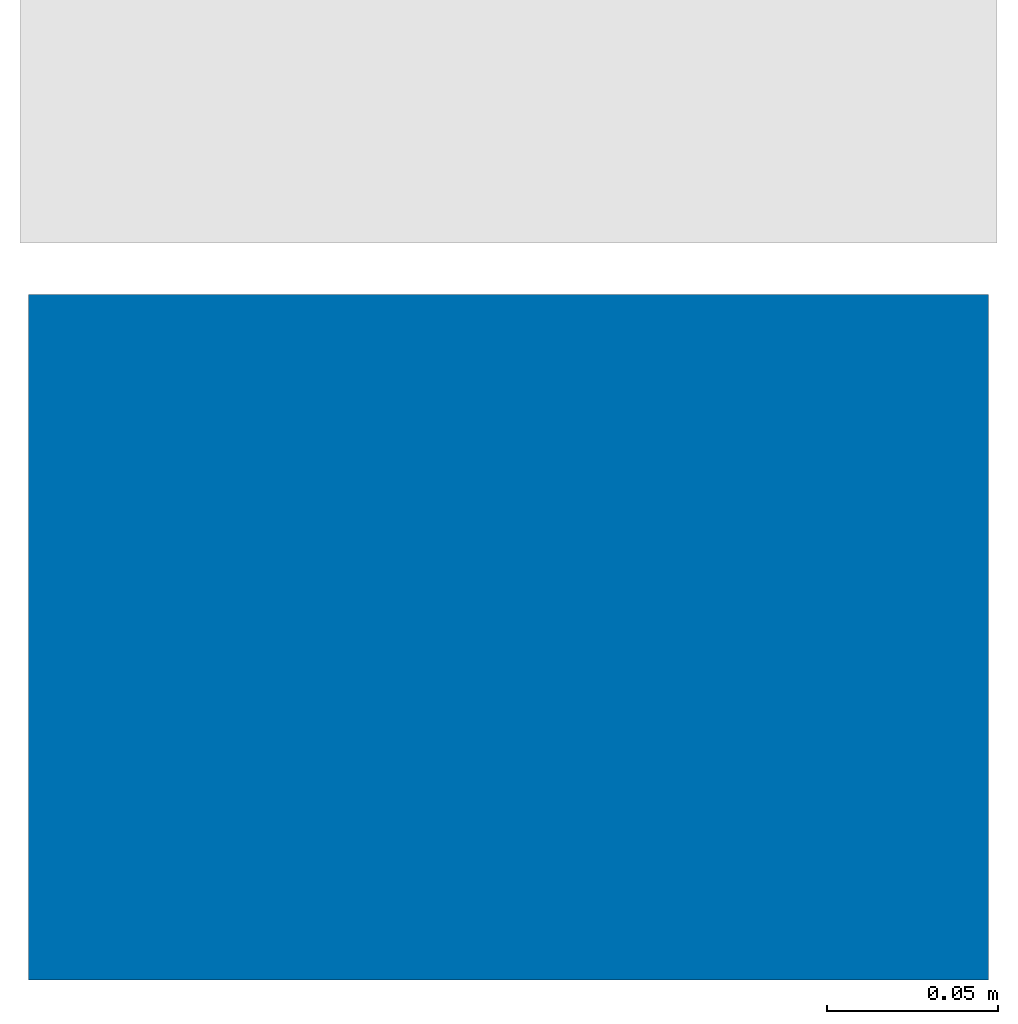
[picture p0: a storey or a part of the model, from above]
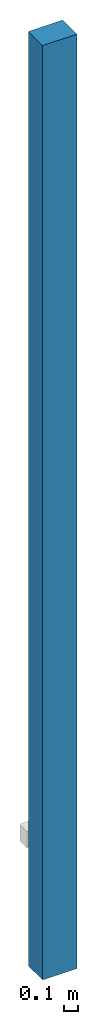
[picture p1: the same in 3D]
Properties of the parts of a building model (IFC2X3)

# File
Description: ViewDefinition [CoordinationView]
File name: Project Number
Time: 2017-11-08T12:43:37
Written by: The EXPRESS Data Manager Version 5.02.0100.07 : 28 Aug 2013
Made in: 20140606_1530(x64) - Exporter 2015.0.2014.0606 - Default UI
Comment: STEP Physical File produced by: The EXPRESS Data Manager Version 5.02.0100.07 : 28 Aug 2013 * Module: EDMstepFileFactory/EDMstandAlone * Creation date: Wed Nov 08 12:43:37 2017 * Host: DESKTOP-FI6EGIK * Database: C:\Users\CERTIF~1\AppData\Local\Temp\{4086A7C5-652F-4AB4-8ED6-AFAA93B8A9EB}\ifc * Database version: 5507 * Database creation date: Wed Nov 08 12:43:37 2017 * Schema: IFC2X3 * Model: DataRepository.ifc * Model creation date: Wed Nov 08 12:43:37 2017 * Header model: DataRepository.ifc_HeaderModel * Header model creation date: Wed Nov 08 12:43:37 2017 * EDMuser: sdai-user * EDMgroup: sdai-group * License ID and type: 5605 : Permanent license. Expiry date: * EDMstepFileFactory options: 020000

# IfcProject, Project Number
LongName: Project Name; Phase: Project Status

# IfcSite, Default
RefLatitude: 42, 21, 30, 344238; RefLongitude: -71, -3, -35, -194702; RefElevation: 0 mm
Other - Category: Project Information; Client Name: Owner; Project Address: ## Street City, State Zip; Project Issue Date: Issue Date; Project Name: Project Name; Project Number: Project Number; Project Status: Project Status

# IfcBuilding
Pset_BuildingCommon - NumberOfStoreys: 1
Other - Category: Project Information; Client Name: Owner; Project Address: ## Street City, State Zip; Project Issue Date: Issue Date; Project Name: Project Name; Project Number: Project Number; Project Status: Project Status

# IfcBuildingStorey, Level 1
LongName: Level 1; Elevation: 0 mm
Other - Category: Levels; Family Name: Level; Family: Level: 8mm Head; Family and Type: Level: 8mm Head; Type: Level: 8mm Head; Type Id: Level: 8mm Head
Identity Data - Type Name: 8mm Head; Structural: no; Building Story: yes; Name: Level 1
Constraints - Elevation: 0 mm; Elevation Base: Project Base Point
Dimensions - Computation Height: 0 mm
Graphics - Color: 0; Line Pattern: Center; Line Weight: 1; Symbol: M_Level Head - Circle: M_Level Head - Circle; Symbol at End 1 Default: no; Symbol at End 2 Default: yes

# IfcBuildingElementProxy: d_line_Washroom_WallMountedSanitaryPanels_TissueDispenser, 14709102000bb:d_line_Washroom_WallMountedSanitaryPanels_TissueDispenser:194047
In: Level 1
Pset_BuildingElementProxyCommon - Reference: d_line_Washroom_WallMountedSanitaryPanels_TissueDispenser
Pset_ManufacturerTypeInformation - ModelReference: n/a; Manufacturer: info@dline.com
Constraints - Elevation: 1000 mm; Level: Level: Level 1
Dimensions - Area: 0.0938791 m2; PlacementHeight: 1000 mm; Volume: 0.00402276 m3; BendRadius: 15 mm; SheetThickness: 2 mm; WallClearance: 15 mm
Other - AssetIdentifier: n/a; BarCode: n/a; Category: Generic Models; Family: 14709102000bb: d_line_Washroom_WallMountedSanitaryPanels_TissueDispenser; Family and Type: 14709102000bb: d_line_Washroom_WallMountedSanitaryPanels_TissueDispenser; Host Id: Basic Wall: Generic - 200mm; InstallationDate: 1900-12-31T23:59:59; SerialNumber: n/a; Type: 14709102000bb: d_line_Washroom_WallMountedSanitaryPanels_TissueDispenser; Type Id: 14709102000bb: d_line_Washroom_WallMountedSanitaryPanels_TissueDispenser; WarrantyStartDate: 1900-12-31T23:59:59; AccessibilityPerformance: n/a; AssetType: Fixed; CodePerformance: n/a; Color: Silver; Constituents: Tissue dispenser; DurationUnit: years; ExpectedLife: 20 years; Family Name: 14709102000bb; Features: n/a; Finish: Polished/Satin; Grade: n/a; Material: Stainless steel AISI 316; ModelNumber: n/a; ModelReference: n/a; Name: d_line_Washroom_WallMountedSanitaryPanels_TissueDispenser; ReplacementCost: n/a; Shape: n/a; Size: 123 x 140 x 285 mm; SustainabilityPerformance: n/a; TagNumber: n/a; WarrantyDescription: 20 years (non-mechanical/-electronic parts) excluding labor; WarrantyDurationLabor: n/a; WarrantyDurationParts: 20; WarrantyDurationUnit: year; WarrantyGuarantorLabor: n/a; WarrantyGuarantorParts: claim@dline.com
Phasing - Phase Created: New Construction
Data - Form: Wall Mounted; IntegralAccessories: n/a; Operation: Manual
General - Author: Gytautas Balevicius; BIMObjectName: d_line_Washroom_WallMountedSanitaryPanels_TissueDispenser; DesignCountry: Denmark; ManufacturerName: d line; ManufacturerURL: www.dline.com; MasterFormat2014Code: 10 28 13; MasterFormat2014Description: Toilet Accessories; NBSCertification: n/a; NBSDescription: n/a; NBSNote: n/a; NBSOfficeMasterTag: n/a; NBSReference: n/a; NBSTypeID: n/a; OmniclassCode: 23-21 21 25 29; OmniclassDescription: Commercial Cup Dispensers; ProductFamily: Sanitary Panels; ProductGroup: Wall mounted panels; ProductInformation: http://dline.com/product/knud-holscher-collection-paper-dispenser/?attribute_pa_material=satin-stainless-steel-aisi-316&attribute_pa_item=wall-mounted-satin-finish#; ProductionCountry: Lithuania; ProductSKU: 14709102000; Revision: n/a; Uniclass2015Code: Pr_40_70_22; Uniclass2015Title: Dispensers and acceptance units; Uniclass2015Version: Products v1.5; UNSPSCCode: 30181500; Version: 1; Weight Net (Kg): 0
Identity Data - Description: Wall mounted tissue dispenser; Manufacturer: info@dline.com; Type Image: Raster image: Image.jpg; Type Name: d_line_Washroom_WallMountedSanitaryPanels_TissueDispenser; URL: www.dline.com
Materials and Finishes - MainMaterial: AISI 316

# IfcWallStandardCase: Basic Wall:Generic - 200mm, Basic Wall:Generic - 200mm:193146
In: Level 1
Type - PredefinedType: STANDARD; Material: Default Wall 200 mm
Type - Analytical Properties - Absorptance: 0.1; Roughness: 1
Type - Construction - Function: Exterior; Width: 200 mm; Wrapping at Inserts: Do not wrap
Type - Graphics - Coarse Scale Fill Color: 0
Type - Identity Data - Type Name: Generic - 200mm
Type - Other - Category: Walls; Family Name: Basic Wall
Constraints - Base Constraint: Level: Level 1; Base Extension Distance: 0 mm; Base is Attached: no; Base Offset: 0 mm; Location Line: Wall Centerline; Related to Mass: no; Room Bounding: yes; Top Extension Distance: 0 mm; Top is Attached: no; Top Offset: 0 mm; Unconnected Height: 8000 mm
Dimensions - Area: 2.24 m2; Length: 280 mm; Volume: 0.448 m3
Other - Family: Basic Wall: Generic - 200mm; Family and Type: Basic Wall: Generic - 200mm; Type: Basic Wall: Generic - 200mm; Type Id: Basic Wall: Generic - 200mm
Phasing - Phase Created: New Construction
Structural - Enable Analytical Model: no; Structural: no; Structural Usage: Non-bearing
Pset_WallCommon - Reference: Generic - 200mm; LoadBearing: no; ExtendToStructure: no; IsExternal: yes
